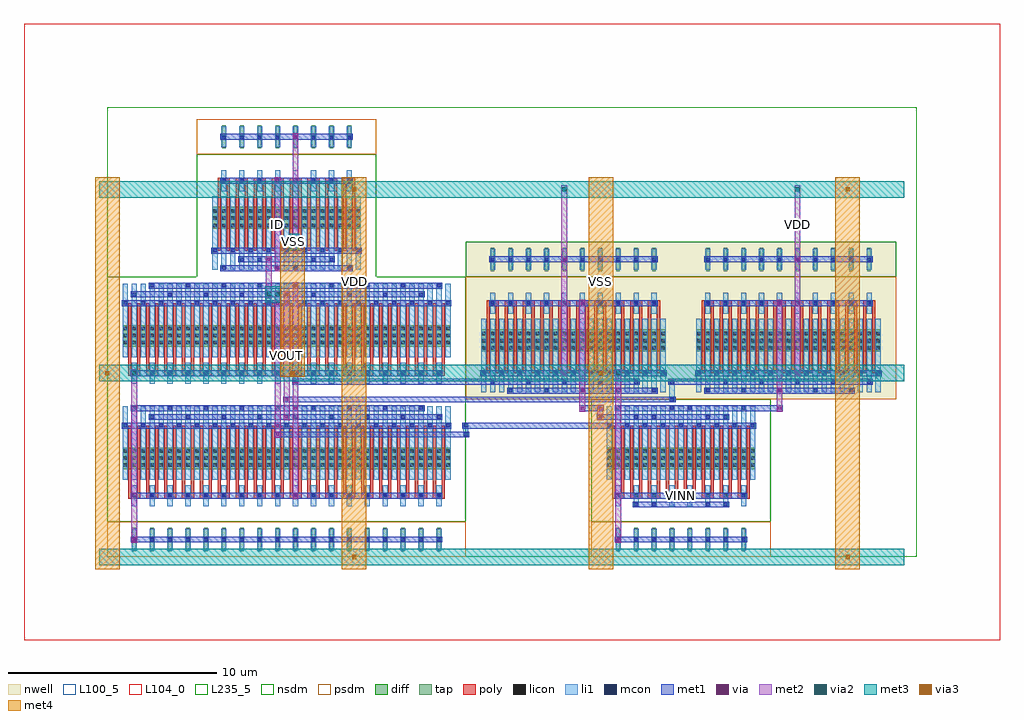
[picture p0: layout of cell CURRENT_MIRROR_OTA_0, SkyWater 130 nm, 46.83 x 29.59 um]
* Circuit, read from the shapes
.subckt CURRENT_MIRROR_OTA_0 ID VDD VINN VINP VOUT VSS
XM1 n1 n1 n2 VSS sky130_fd_pr__nfet_01v8 w=1.05 l=0.15 m=36
XM2 VOUT n1 n2 VSS sky130_fd_pr__nfet_01v8 w=1.05 l=0.15 m=36
XM3 ID ID VSS VSS sky130_fd_pr__nfet_01v8 w=1.05 l=0.15 m=8
XM4 n2 ID VSS VSS sky130_fd_pr__nfet_01v8 w=1.05 l=0.15 m=8
XM5 n3 VINN n2 VSS sky130_fd_pr__nfet_01v8 w=1.05 l=0.15 m=8
XM6 n4 VINP n2 VSS sky130_fd_pr__nfet_01v8 w=1.05 l=0.15 m=8
XM7 n1 n4 VDD VDD sky130_fd_pr__pfet_01v8 w=1.05 l=0.15 m=10
XM8 n4 n4 VDD VDD sky130_fd_pr__pfet_01v8 w=1.05 l=0.15 m=10
XM9 n3 n3 VDD VDD sky130_fd_pr__pfet_01v8 w=1.05 l=0.15 m=10
XM10 VOUT n3 VDD VDD sky130_fd_pr__pfet_01v8 w=1.05 l=0.15 m=10
.ends

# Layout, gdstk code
from math import pi, radians
import gdstk
lib = gdstk.Library(unit=1e-6, precision=1e-09)
def R(c, l, rs):  # rectangles x0, y0, x1, y1
    for r in rs: c.add(gdstk.rectangle(r[:2], r[2:], *l))
def A(c, l, x, y, w, h, nx, ny, dx, dy):  # array of equal rectangles
    R(c, l, [(x+i*dx, y+j*dy, x+i*dx+w, y+j*dy+h) for i in range(nx) for j in range(ny)])
def P(c, l, *ps):  # polygons
    for p in ps: c.add(gdstk.Polygon(p, *l))
nwell = (64, 20)
diff = (65, 20)
tap = (65, 44)
poly = (66, 20)
licon = (66, 44)
li1 = (67, 20)
mcon = (67, 44)
met1 = (68, 20)
via = (68, 44)
met2 = (69, 20)
via2 = (69, 44)
met3 = (70, 20)
via3 = (70, 44)
met4 = (71, 20)
nsdm = (93, 44)
psdm = (94, 20)
L100_5 = (100, 5)
L104_0 = (104, 0)
L235_5 = (235, 5)

scm_nmos_38434623_x4_y1_ = lib.new_cell('SCM_NMOS_38434623_X4_Y1_1725058283')
R(scm_nmos_38434623_x4_y1_, diff, [(0.735,2.31,7.865,3.36)])
A(scm_nmos_38434623_x4_y1_, tap, 1.205, 6.16, 0.17, 1.12, 8, 1, 0.86, 0)
A(scm_nmos_38434623_x4_y1_, poly, 1, 1.26, 0.15, 3.36, 16, 1, 0.43, 0)
A(scm_nmos_38434623_x4_y1_, poly, 1, 4.485, 0.58, 0.27, 8, 1, 0.86, 0)
A(scm_nmos_38434623_x4_y1_, licon, 0.775, 2.39, 0.17, 0.17, 3, 3, 0.43, 0.34)
A(scm_nmos_38434623_x4_y1_, licon, 1.635, 2.39, 0.17, 0.17, 3, 3, 0.43, 0.34)
A(scm_nmos_38434623_x4_y1_, licon, 2.495, 2.39, 0.17, 0.17, 3, 3, 0.43, 0.34)
A(scm_nmos_38434623_x4_y1_, licon, 3.355, 2.39, 0.17, 0.17, 3, 3, 0.43, 0.34)
A(scm_nmos_38434623_x4_y1_, licon, 4.215, 2.39, 0.17, 0.17, 3, 3, 0.43, 0.34)
A(scm_nmos_38434623_x4_y1_, licon, 5.075, 2.39, 0.17, 0.17, 3, 3, 0.43, 0.34)
A(scm_nmos_38434623_x4_y1_, licon, 5.935, 2.39, 0.17, 0.17, 3, 3, 0.43, 0.34)
A(scm_nmos_38434623_x4_y1_, licon, 6.795, 2.39, 0.17, 0.17, 3, 3, 0.43, 0.34)
A(scm_nmos_38434623_x4_y1_, licon, 1.205, 4.535, 0.17, 0.17, 8, 2, 0.86, 2.1)
A(scm_nmos_38434623_x4_y1_, li1, 0.735, 0.335, 0.25, 3.53, 17, 1, 0.43, 0)
A(scm_nmos_38434623_x4_y1_, li1, 1.165, 4.115, 0.25, 1.01, 8, 2, 0.86, 2.1)
A(scm_nmos_38434623_x4_y1_, mcon, 0.775, 1.175, 0.17, 0.17, 9, 1, 0.86, 0)
A(scm_nmos_38434623_x4_y1_, mcon, 1.205, 4.535, 0.17, 0.17, 8, 2, 0.86, 2.1)
R(scm_nmos_38434623_x4_y1_, mcon, [(1.205,0.335,1.375,0.505), (3.785,0.335,3.955,0.505), (4.645,0.335,4.815,0.505), (7.225,0.335,7.395,0.505), (2.065,0.755,2.235,0.925), (2.925,0.755,3.095,0.925), (5.505,0.755,5.675,0.925), (6.365,0.755,6.535,0.925)])
R(scm_nmos_38434623_x4_y1_, met1, [(1.12,0.28,7.48,0.56), (1.98,0.7,6.62,0.98), (0.69,1.12,7.91,1.4), (1.12,4.48,7.48,4.76), (1.12,6.58,7.48,6.86)])
R(scm_nmos_38434623_x4_y1_, via, [(3.795,0.345,3.945,0.495), (4.655,1.185,4.805,1.335), (3.795,4.545,3.945,4.695), (4.655,6.645,4.805,6.795)])
R(scm_nmos_38434623_x4_y1_, met2, [(3.73,0.26,4.01,4.78), (4.59,1.1,4.87,6.88)])
R(scm_nmos_38434623_x4_y1_, nsdm, [(0,0,8.6,5.88)])
R(scm_nmos_38434623_x4_y1_, psdm, [(0,5.88,8.6,7.56)])
R(scm_nmos_38434623_x4_y1_, L100_5, [(0,0,8.6,7.56)])

scm_pmos_61005845_x5_y1_ = lib.new_cell('SCM_PMOS_61005845_X5_Y1_1725058285')
R(scm_pmos_61005845_x5_y1_, nwell, [(0,0,10.32,7.56)])
R(scm_pmos_61005845_x5_y1_, diff, [(0.735,2.31,9.585,3.36)])
A(scm_pmos_61005845_x5_y1_, tap, 1.205, 6.16, 0.17, 1.12, 10, 1, 0.86, 0)
A(scm_pmos_61005845_x5_y1_, poly, 1, 1.26, 0.15, 3.36, 20, 1, 0.43, 0)
A(scm_pmos_61005845_x5_y1_, poly, 1, 4.485, 0.58, 0.27, 10, 1, 0.86, 0)
A(scm_pmos_61005845_x5_y1_, licon, 0.775, 2.39, 0.17, 0.17, 3, 3, 0.43, 0.34)
A(scm_pmos_61005845_x5_y1_, licon, 1.635, 2.39, 0.17, 0.17, 3, 3, 0.43, 0.34)
A(scm_pmos_61005845_x5_y1_, licon, 2.495, 2.39, 0.17, 0.17, 3, 3, 0.43, 0.34)
A(scm_pmos_61005845_x5_y1_, licon, 3.355, 2.39, 0.17, 0.17, 3, 3, 0.43, 0.34)
A(scm_pmos_61005845_x5_y1_, licon, 4.215, 2.39, 0.17, 0.17, 3, 3, 0.43, 0.34)
A(scm_pmos_61005845_x5_y1_, licon, 5.075, 2.39, 0.17, 0.17, 3, 3, 0.43, 0.34)
A(scm_pmos_61005845_x5_y1_, licon, 5.935, 2.39, 0.17, 0.17, 3, 3, 0.43, 0.34)
A(scm_pmos_61005845_x5_y1_, licon, 6.795, 2.39, 0.17, 0.17, 3, 3, 0.43, 0.34)
A(scm_pmos_61005845_x5_y1_, licon, 7.655, 2.39, 0.17, 0.17, 3, 3, 0.43, 0.34)
A(scm_pmos_61005845_x5_y1_, licon, 8.515, 2.39, 0.17, 0.17, 3, 3, 0.43, 0.34)
A(scm_pmos_61005845_x5_y1_, licon, 1.205, 4.535, 0.17, 0.17, 10, 2, 0.86, 2.1)
A(scm_pmos_61005845_x5_y1_, li1, 0.735, 0.335, 0.25, 3.53, 21, 1, 0.43, 0)
A(scm_pmos_61005845_x5_y1_, li1, 1.165, 4.115, 0.25, 1.01, 10, 2, 0.86, 2.1)
A(scm_pmos_61005845_x5_y1_, mcon, 1.205, 0.335, 0.17, 0.17, 5, 1, 1.72, 0)
A(scm_pmos_61005845_x5_y1_, mcon, 2.065, 0.755, 0.17, 0.17, 5, 1, 1.72, 0)
A(scm_pmos_61005845_x5_y1_, mcon, 0.775, 1.175, 0.17, 0.17, 11, 1, 0.86, 0)
A(scm_pmos_61005845_x5_y1_, mcon, 1.205, 4.535, 0.17, 0.17, 10, 2, 0.86, 2.1)
R(scm_pmos_61005845_x5_y1_, met1, [(1.12,0.28,8.34,0.56), (1.98,0.7,9.2,0.98), (0.69,1.12,9.63,1.4), (1.12,4.48,9.2,4.76), (1.12,6.58,9.2,6.86)])
R(scm_pmos_61005845_x5_y1_, via, [(4.655,0.345,4.805,0.495), (5.515,1.185,5.665,1.335), (4.655,4.545,4.805,4.695), (5.515,6.645,5.665,6.795)])
R(scm_pmos_61005845_x5_y1_, met2, [(4.59,0.26,4.87,4.78), (5.45,1.1,5.73,6.88)])
R(scm_pmos_61005845_x5_y1_, nsdm, [(0,5.88,10.32,7.56)])
R(scm_pmos_61005845_x5_y1_, psdm, [(0,0,10.32,5.88)])
R(scm_pmos_61005845_x5_y1_, L100_5, [(0,0,10.32,7.56)])

scm_nmos_b_8106910_x9_y2 = lib.new_cell('SCM_NMOS_B_8106910_X9_Y2_1725058284')
R(scm_nmos_b_8106910_x9_y2, diff, [(0.735,2.31,16.465,3.36), (0.735,8.19,16.465,9.24)])
A(scm_nmos_b_8106910_x9_y2, tap, 1.205, 12.04, 0.17, 1.12, 18, 1, 0.86, 0)
A(scm_nmos_b_8106910_x9_y2, poly, 1, 1.26, 0.15, 3.36, 36, 2, 0.43, 5.88)
A(scm_nmos_b_8106910_x9_y2, poly, 1, 4.485, 0.58, 0.27, 18, 2, 0.86, 5.88)
A(scm_nmos_b_8106910_x9_y2, licon, 0.775, 2.39, 0.17, 0.17, 3, 3, 0.43, 0.34)
A(scm_nmos_b_8106910_x9_y2, licon, 1.635, 2.39, 0.17, 0.17, 3, 3, 0.43, 0.34)
A(scm_nmos_b_8106910_x9_y2, licon, 2.495, 2.39, 0.17, 0.17, 3, 3, 0.43, 0.34)
A(scm_nmos_b_8106910_x9_y2, licon, 3.355, 2.39, 0.17, 0.17, 3, 3, 0.43, 0.34)
A(scm_nmos_b_8106910_x9_y2, licon, 4.215, 2.39, 0.17, 0.17, 3, 3, 0.43, 0.34)
A(scm_nmos_b_8106910_x9_y2, licon, 5.075, 2.39, 0.17, 0.17, 3, 3, 0.43, 0.34)
A(scm_nmos_b_8106910_x9_y2, licon, 5.935, 2.39, 0.17, 0.17, 3, 3, 0.43, 0.34)
A(scm_nmos_b_8106910_x9_y2, licon, 6.795, 2.39, 0.17, 0.17, 3, 3, 0.43, 0.34)
A(scm_nmos_b_8106910_x9_y2, licon, 7.655, 2.39, 0.17, 0.17, 3, 3, 0.43, 0.34)
A(scm_nmos_b_8106910_x9_y2, licon, 8.515, 2.39, 0.17, 0.17, 3, 3, 0.43, 0.34)
A(scm_nmos_b_8106910_x9_y2, licon, 9.375, 2.39, 0.17, 0.17, 3, 3, 0.43, 0.34)
A(scm_nmos_b_8106910_x9_y2, licon, 10.235, 2.39, 0.17, 0.17, 3, 3, 0.43, 0.34)
A(scm_nmos_b_8106910_x9_y2, licon, 11.095, 2.39, 0.17, 0.17, 3, 3, 0.43, 0.34)
A(scm_nmos_b_8106910_x9_y2, licon, 11.955, 2.39, 0.17, 0.17, 3, 3, 0.43, 0.34)
A(scm_nmos_b_8106910_x9_y2, licon, 12.815, 2.39, 0.17, 0.17, 3, 3, 0.43, 0.34)
A(scm_nmos_b_8106910_x9_y2, licon, 13.675, 2.39, 0.17, 0.17, 3, 3, 0.43, 0.34)
A(scm_nmos_b_8106910_x9_y2, licon, 14.535, 2.39, 0.17, 0.17, 3, 3, 0.43, 0.34)
A(scm_nmos_b_8106910_x9_y2, licon, 15.395, 2.39, 0.17, 0.17, 3, 3, 0.43, 0.34)
A(scm_nmos_b_8106910_x9_y2, licon, 1.205, 4.535, 0.17, 0.17, 18, 2, 0.86, 5.88)
A(scm_nmos_b_8106910_x9_y2, licon, 0.775, 8.27, 0.17, 0.17, 3, 3, 0.43, 0.34)
A(scm_nmos_b_8106910_x9_y2, licon, 1.635, 8.27, 0.17, 0.17, 3, 3, 0.43, 0.34)
A(scm_nmos_b_8106910_x9_y2, licon, 2.495, 8.27, 0.17, 0.17, 3, 3, 0.43, 0.34)
A(scm_nmos_b_8106910_x9_y2, licon, 3.355, 8.27, 0.17, 0.17, 3, 3, 0.43, 0.34)
A(scm_nmos_b_8106910_x9_y2, licon, 4.215, 8.27, 0.17, 0.17, 3, 3, 0.43, 0.34)
A(scm_nmos_b_8106910_x9_y2, licon, 5.075, 8.27, 0.17, 0.17, 3, 3, 0.43, 0.34)
A(scm_nmos_b_8106910_x9_y2, licon, 5.935, 8.27, 0.17, 0.17, 3, 3, 0.43, 0.34)
A(scm_nmos_b_8106910_x9_y2, licon, 6.795, 8.27, 0.17, 0.17, 3, 3, 0.43, 0.34)
A(scm_nmos_b_8106910_x9_y2, licon, 7.655, 8.27, 0.17, 0.17, 3, 3, 0.43, 0.34)
A(scm_nmos_b_8106910_x9_y2, licon, 8.515, 8.27, 0.17, 0.17, 3, 3, 0.43, 0.34)
A(scm_nmos_b_8106910_x9_y2, licon, 9.375, 8.27, 0.17, 0.17, 3, 3, 0.43, 0.34)
A(scm_nmos_b_8106910_x9_y2, licon, 10.235, 8.27, 0.17, 0.17, 3, 3, 0.43, 0.34)
A(scm_nmos_b_8106910_x9_y2, licon, 11.095, 8.27, 0.17, 0.17, 3, 3, 0.43, 0.34)
A(scm_nmos_b_8106910_x9_y2, licon, 11.955, 8.27, 0.17, 0.17, 3, 3, 0.43, 0.34)
A(scm_nmos_b_8106910_x9_y2, licon, 12.815, 8.27, 0.17, 0.17, 3, 3, 0.43, 0.34)
A(scm_nmos_b_8106910_x9_y2, licon, 13.675, 8.27, 0.17, 0.17, 3, 3, 0.43, 0.34)
A(scm_nmos_b_8106910_x9_y2, licon, 14.535, 8.27, 0.17, 0.17, 3, 3, 0.43, 0.34)
A(scm_nmos_b_8106910_x9_y2, licon, 15.395, 8.27, 0.17, 0.17, 3, 3, 0.43, 0.34)
R(scm_nmos_b_8106910_x9_y2, licon, [(1.205,12.515,1.375,12.685), (1.205,12.515,1.375,12.685), (2.065,12.515,2.235,12.685), (2.065,12.515,2.235,12.685), (2.925,12.515,3.095,12.685), (2.925,12.515,3.095,12.685), (3.785,12.515,3.955,12.685), (3.785,12.515,3.955,12.685), (4.645,12.515,4.815,12.685), (4.645,12.515,4.815,12.685), (5.505,12.515,5.675,12.685), (5.505,12.515,5.675,12.685), (6.365,12.515,6.535,12.685), (6.365,12.515,6.535,12.685), (7.225,12.515,7.395,12.685), (7.225,12.515,7.395,12.685), (8.085,12.515,8.255,12.685), (8.085,12.515,8.255,12.685), (8.945,12.515,9.115,12.685), (8.945,12.515,9.115,12.685), (9.805,12.515,9.975,12.685), (9.805,12.515,9.975,12.685), (10.665,12.515,10.835,12.685), (10.665,12.515,10.835,12.685), (11.525,12.515,11.695,12.685), (11.525,12.515,11.695,12.685), (12.385,12.515,12.555,12.685), (12.385,12.515,12.555,12.685), (13.245,12.515,13.415,12.685), (13.245,12.515,13.415,12.685), (14.105,12.515,14.275,12.685), (14.105,12.515,14.275,12.685), (14.965,12.515,15.135,12.685), (14.965,12.515,15.135,12.685), (15.825,12.515,15.995,12.685), (15.825,12.515,15.995,12.685)])
A(scm_nmos_b_8106910_x9_y2, li1, 0.735, 0.335, 0.25, 3.53, 37, 2, 0.43, 5.88)
A(scm_nmos_b_8106910_x9_y2, li1, 1.165, 4.115, 0.25, 1.01, 18, 2, 0.86, 5.88)
A(scm_nmos_b_8106910_x9_y2, li1, 1.165, 12.095, 0.25, 1.01, 18, 1, 0.86, 0)
A(scm_nmos_b_8106910_x9_y2, mcon, 1.205, 0.335, 0.17, 0.17, 9, 2, 1.72, 6.3)
A(scm_nmos_b_8106910_x9_y2, mcon, 2.065, 0.755, 0.17, 0.17, 9, 2, 1.72, 5.46)
A(scm_nmos_b_8106910_x9_y2, mcon, 0.775, 1.175, 0.17, 0.17, 19, 2, 0.86, 5.88)
A(scm_nmos_b_8106910_x9_y2, mcon, 1.205, 4.535, 0.17, 0.17, 18, 2, 0.86, 5.88)
A(scm_nmos_b_8106910_x9_y2, mcon, 1.205, 12.515, 0.17, 0.17, 18, 1, 0.86, 0)
R(scm_nmos_b_8106910_x9_y2, met1, [(1.12,0.28,15.22,0.56), (1.98,0.7,16.08,0.98), (0.69,1.12,16.51,1.4), (1.12,4.48,16.08,4.76), (1.98,6.16,16.08,6.44), (1.12,6.58,15.22,6.86), (0.69,7,16.51,7.28), (1.12,10.36,16.08,10.64), (1.12,12.46,16.08,12.74)])
R(scm_nmos_b_8106910_x9_y2, via, [(8.095,0.345,8.245,0.495), (8.525,0.765,8.675,0.915), (8.955,1.185,9.105,1.335), (8.095,4.545,8.245,4.695), (8.095,6.225,8.245,6.375), (8.525,6.645,8.675,6.795), (8.955,7.065,9.105,7.215), (8.095,10.425,8.245,10.575)])
R(scm_nmos_b_8106910_x9_y2, met2, [(8.03,0.26,8.31,10.66), (8.46,0.68,8.74,6.88), (8.89,1.1,9.17,7.3)])
R(scm_nmos_b_8106910_x9_y2, nsdm, [(0,0,17.2,11.76)])
R(scm_nmos_b_8106910_x9_y2, psdm, [(0,11.76,17.2,13.44)])
R(scm_nmos_b_8106910_x9_y2, L100_5, [(0,0,17.2,13.44)])

dp_nmos_b_13499319_x4_y1 = lib.new_cell('DP_NMOS_B_13499319_X4_Y1_1725058282')
R(dp_nmos_b_13499319_x4_y1, diff, [(0.735,2.31,7.865,3.36)])
A(dp_nmos_b_13499319_x4_y1, tap, 1.205, 6.16, 0.17, 1.12, 8, 1, 0.86, 0)
A(dp_nmos_b_13499319_x4_y1, poly, 1, 1.26, 0.15, 3.36, 16, 1, 0.43, 0)
A(dp_nmos_b_13499319_x4_y1, poly, 1, 4.485, 0.58, 0.27, 8, 1, 0.86, 0)
A(dp_nmos_b_13499319_x4_y1, licon, 0.775, 2.39, 0.17, 0.17, 3, 3, 0.43, 0.34)
A(dp_nmos_b_13499319_x4_y1, licon, 1.635, 2.39, 0.17, 0.17, 3, 3, 0.43, 0.34)
A(dp_nmos_b_13499319_x4_y1, licon, 2.495, 2.39, 0.17, 0.17, 3, 3, 0.43, 0.34)
A(dp_nmos_b_13499319_x4_y1, licon, 3.355, 2.39, 0.17, 0.17, 3, 3, 0.43, 0.34)
A(dp_nmos_b_13499319_x4_y1, licon, 4.215, 2.39, 0.17, 0.17, 3, 3, 0.43, 0.34)
A(dp_nmos_b_13499319_x4_y1, licon, 5.075, 2.39, 0.17, 0.17, 3, 3, 0.43, 0.34)
A(dp_nmos_b_13499319_x4_y1, licon, 5.935, 2.39, 0.17, 0.17, 3, 3, 0.43, 0.34)
A(dp_nmos_b_13499319_x4_y1, licon, 6.795, 2.39, 0.17, 0.17, 3, 3, 0.43, 0.34)
A(dp_nmos_b_13499319_x4_y1, licon, 1.205, 4.535, 0.17, 0.17, 8, 2, 0.86, 2.1)
A(dp_nmos_b_13499319_x4_y1, li1, 0.735, 0.335, 0.25, 3.53, 17, 1, 0.43, 0)
A(dp_nmos_b_13499319_x4_y1, li1, 1.165, 4.115, 0.25, 1.01, 8, 2, 0.86, 2.1)
A(dp_nmos_b_13499319_x4_y1, mcon, 0.775, 1.175, 0.17, 0.17, 9, 1, 0.86, 0)
A(dp_nmos_b_13499319_x4_y1, mcon, 1.205, 6.635, 0.17, 0.17, 8, 1, 0.86, 0)
R(dp_nmos_b_13499319_x4_y1, mcon, [(1.205,0.335,1.375,0.505), (3.785,0.335,3.955,0.505), (4.645,0.335,4.815,0.505), (7.225,0.335,7.395,0.505), (2.065,0.755,2.235,0.925), (2.925,0.755,3.095,0.925), (5.505,0.755,5.675,0.925), (6.365,0.755,6.535,0.925), (1.205,4.535,1.375,4.705), (3.785,4.535,3.955,4.705), (4.645,4.535,4.815,4.705), (7.225,4.535,7.395,4.705), (2.065,4.955,2.235,5.125), (2.925,4.955,3.095,5.125), (5.505,4.955,5.675,5.125), (6.365,4.955,6.535,5.125)])
R(dp_nmos_b_13499319_x4_y1, met1, [(1.12,0.28,7.48,0.56), (1.98,0.7,6.62,0.98), (0.69,1.12,7.91,1.4), (1.12,4.48,7.48,4.76), (1.98,4.9,6.62,5.18), (1.12,6.58,7.48,6.86)])
R(dp_nmos_b_13499319_x4_y1, nsdm, [(0,0,8.6,5.88)])
R(dp_nmos_b_13499319_x4_y1, psdm, [(0,5.88,8.6,7.56)])
R(dp_nmos_b_13499319_x4_y1, L100_5, [(0,0,8.6,7.56)])

current_mirror_ota_0 = lib.new_cell('CURRENT_MIRROR_OTA_0')
R(current_mirror_ota_0, li1, [(17.075,5.795,17.325,5.965), (17.075,5.795,17.325,5.965), (17.075,5.88,17.325,6.3), (17.075,6.215,17.325,6.385), (17.075,6.215,17.325,6.385), (26.965,7.475,27.215,7.645), (26.965,7.475,27.215,7.645), (26.965,7.56,27.215,8.4), (26.965,8.315,27.215,8.485), (26.965,8.315,27.215,8.485)])
R(current_mirror_ota_0, mcon, [(17.115,5.795,17.285,5.965), (17.115,5.795,17.285,5.965), (17.115,6.215,17.285,6.385), (17.115,6.215,17.285,6.385), (27.005,7.475,27.175,7.645), (27.005,7.475,27.175,7.645), (27.005,8.315,27.175,8.485), (27.005,8.315,27.175,8.485)])
R(current_mirror_ota_0, met1, [(1.13,0.7,1.45,0.98), (1.13,0.7,1.45,0.98), (1.13,0.7,1.45,0.98), (24.35,0.7,24.67,0.98), (24.35,0.7,24.67,0.98), (8.01,5.74,8.33,6.02), (8.01,5.74,8.33,6.02), (8.17,5.74,17.2,6.02), (17.03,5.74,17.37,6.02), (17.03,5.74,17.37,6.02), (17.03,6.16,17.37,6.44), (17.03,6.16,17.37,6.44), (17.2,6.16,24.08,6.44), (23.49,6.58,23.81,6.86), (23.49,6.58,23.81,6.86), (23.65,6.58,25.37,6.86), (22.63,7,22.95,7.28), (22.63,7,22.95,7.28), (22.79,7,23.65,7.28), (23.49,7,23.81,7.28), (23.49,7,23.81,7.28), (30.53,7,32.25,7.28), (32.09,7,32.41,7.28), (32.09,7,32.41,7.28), (8.44,7.42,8.76,7.7), (8.44,7.42,8.76,7.7), (8.6,7.42,27.09,7.7), (26.92,7.42,27.26,7.7), (26.92,7.42,27.26,7.7), (8.87,8.26,9.19,8.54), (8.87,8.26,9.19,8.54), (9.03,8.26,18.49,8.54), (26.92,8.26,27.26,8.54), (26.92,8.26,27.26,8.54), (27.09,8.26,29.67,8.54), (7.58,14.14,7.9,14.42), (7.58,14.14,7.9,14.42), (7.58,14.14,7.9,14.42), (7.58,14.14,7.9,14.42)])
P(current_mirror_ota_0, met1, [(0,0),(0,0),(0,0),(0,0)],
  [(0,0),(0,0),(0,0),(0,0)],
  [(0,0),(0,0),(0,0),(0,0)],
  [(0,0),(0,0),(0,0),(0,0)],
  [(0,0),(0,0),(0,0),(0,0)],
  [(0,0),(0,0),(0,0),(0,0)],
  [(0,0),(0,0),(0,0),(0,0)],
  [(0,0),(0,0),(0,0),(0,0)],
  [(0,0),(0,0),(0,0),(0,0)],
  [(0,0),(0,0),(0,0),(0,0)],
  [(0,0),(0,0),(0,0),(0,0)],
  [(0,0),(0,0),(0,0),(0,0)])
R(current_mirror_ota_0, via, [(1.215,0.765,1.365,0.915), (1.215,0.765,1.365,0.915), (1.215,0.765,1.365,0.915), (24.435,0.765,24.585,0.915), (24.435,0.765,24.585,0.915), (8.095,5.805,8.245,5.955), (8.095,5.805,8.245,5.955), (23.575,6.645,23.725,6.795), (23.575,6.645,23.725,6.795), (22.715,7.065,22.865,7.215), (22.715,7.065,22.865,7.215), (23.575,7.065,23.725,7.215), (23.575,7.065,23.725,7.215), (32.175,7.065,32.325,7.215), (32.175,7.065,32.325,7.215), (8.525,7.485,8.675,7.635), (8.525,7.485,8.675,7.635), (8.955,8.325,9.105,8.475), (8.955,8.325,9.105,8.475), (7.665,14.205,7.815,14.355), (7.665,14.205,7.815,14.355), (7.665,14.205,7.815,14.355), (7.665,14.205,7.815,14.355)])
R(current_mirror_ota_0, met2, [(1.15,0.68,1.43,1), (1.15,0.68,1.43,1), (1.15,0.68,1.43,1), (24.37,0.68,24.65,1), (24.37,0.68,24.65,1), (1.15,0.84,1.43,8.82), (24.37,0.84,24.65,8.82), (8.03,5.72,8.31,6.04), (8.03,5.72,8.31,6.04), (8.03,5.88,8.31,6.3), (23.51,6.56,23.79,6.88), (23.51,6.56,23.79,6.88), (23.51,6.72,23.79,7.14), (22.65,6.98,22.93,7.3), (22.65,6.98,22.93,7.3), (23.51,6.98,23.79,7.3), (23.51,6.98,23.79,7.3), (32.11,6.98,32.39,7.3), (32.11,6.98,32.39,7.3), (22.65,7.14,22.93,7.98), (32.11,7.14,32.39,7.98), (8.46,7.4,8.74,7.72), (8.46,7.4,8.74,7.72), (8.89,8.24,9.17,8.56), (8.89,8.24,9.17,8.56), (1.15,8.635,1.43,9.005), (1.15,8.635,1.43,9.005), (1.15,8.635,1.43,9.005), (24.37,8.635,24.65,9.005), (24.37,8.635,24.65,9.005), (8.03,12.18,8.31,12.6), (7.6,12.415,7.88,12.785), (7.6,12.415,7.88,12.785), (7.6,12.415,7.88,12.785), (7.6,12.415,7.88,12.785), (8.03,12.415,8.31,12.785), (8.03,12.415,8.31,12.785), (8.03,12.415,8.31,12.785), (8.03,12.415,8.31,12.785), (7.6,12.6,7.88,14.28), (7.6,14.12,7.88,14.44), (7.6,14.12,7.88,14.44), (7.6,14.12,7.88,14.44), (7.6,14.12,7.88,14.44), (21.79,14.28,22.07,17.64), (32.97,14.28,33.25,17.64), (8.89,14.935,9.17,15.305), (21.79,17.455,22.07,17.825), (21.79,17.455,22.07,17.825), (32.97,17.455,33.25,17.825), (32.97,17.455,33.25,17.825), (32.97,17.455,33.25,17.825)])
P(current_mirror_ota_0, met2, [(0,0),(0,0),(0,0),(0,0)],
  [(0,0),(0,0),(0,0),(0,0)],
  [(0,0),(0,0),(0,0),(0,0)],
  [(0,0),(0,0),(0,0),(0,0)],
  [(0,0),(0,0),(0,0),(0,0)],
  [(0,0),(0,0),(0,0),(0,0)],
  [(0,0),(0,0),(0,0),(0,0)],
  [(0,0),(0,0),(0,0),(0,0)],
  [(0,0),(0,0),(0,0),(0,0)],
  [(0,0),(0,0),(0,0),(0,0)],
  [(0,0),(0,0),(0,0),(0,0)])
R(current_mirror_ota_0, via2, [(1.19,8.72,1.39,8.92), (1.19,8.72,1.39,8.92), (1.19,8.72,1.39,8.92), (24.41,8.72,24.61,8.92), (24.41,8.72,24.61,8.92), (7.64,12.5,7.84,12.7), (7.64,12.5,7.84,12.7), (7.64,12.5,7.84,12.7), (7.64,12.5,7.84,12.7), (8.07,12.5,8.27,12.7), (8.07,12.5,8.27,12.7), (8.07,12.5,8.27,12.7), (8.07,12.5,8.27,12.7), (8.93,15.02,9.13,15.22), (21.83,17.54,22.03,17.74), (21.83,17.54,22.03,17.74), (33.01,17.54,33.21,17.74), (33.01,17.54,33.21,17.74), (33.01,17.54,33.21,17.74)])
A(current_mirror_ota_0, met3, -0.4, -0.4, 4.24, 0.8, 3, 3, 3.44, 8.82)
A(current_mirror_ota_0, met3, 9.92, -0.4, 2.32, 0.8, 1, 3, 0, 8.82)
A(current_mirror_ota_0, met3, 11.44, -0.4, 2.72, 0.8, 1, 3, 0, 8.82)
A(current_mirror_ota_0, met3, 13.36, -0.4, 4.24, 0.8, 1, 3, 0, 8.82)
A(current_mirror_ota_0, met3, 16.8, -0.4, 4.24, 0.8, 1, 3, 0, 8.82)
A(current_mirror_ota_0, met3, 20.24, -0.4, 3.84, 0.8, 1, 3, 0, 8.82)
A(current_mirror_ota_0, met3, 23.28, -0.4, 1.2, 0.8, 1, 3, 0, 8.82)
A(current_mirror_ota_0, met3, 23.68, -0.4, 4.24, 0.8, 3, 3, 3.44, 8.82)
A(current_mirror_ota_0, met3, 34, -0.4, 1.92, 0.8, 1, 3, 0, 8.82)
A(current_mirror_ota_0, met3, 35.12, -0.4, 3.12, 0.8, 1, 3, 0, 8.82)
R(current_mirror_ota_0, met3, [(11.675,-0.4,12.005,0.4), (35.355,-0.4,35.685,0.4), (-0.165,8.42,0.165,9.22), (1.125,8.42,1.455,9.22), (1.125,8.42,1.455,9.22), (1.125,8.42,1.455,9.22), (8.715,8.42,9.045,9.22), (8.715,8.42,9.045,9.22), (8.715,8.42,9.045,9.22), (8.715,8.42,9.045,9.22), (23.515,8.42,23.845,9.22), (24.345,8.42,24.675,9.22), (24.345,8.42,24.675,9.22), (7.575,12.2,7.905,13), (7.575,12.2,7.905,13), (7.575,12.2,7.905,13), (7.575,12.2,7.905,13), (7.74,12.2,8.17,13), (8.005,12.2,8.335,13), (8.005,12.2,8.335,13), (8.005,12.2,8.335,13), (8.005,12.2,8.335,13), (8.715,14.72,9.045,15.52), (8.805,14.72,9.105,15.52), (8.865,14.72,9.195,15.52), (11.675,17.24,12.005,18.04), (21.765,17.24,22.095,18.04), (21.765,17.24,22.095,18.04), (32.945,17.24,33.275,18.04), (32.945,17.24,33.275,18.04), (32.945,17.24,33.275,18.04), (35.355,17.24,35.685,18.04)])
R(current_mirror_ota_0, via3, [(11.74,-0.1,11.94,0.1), (35.42,-0.1,35.62,0.1), (-0.1,8.72,0.1,8.92), (8.78,8.72,8.98,8.92), (8.78,8.72,8.98,8.92), (8.78,8.72,8.98,8.92), (8.78,8.72,8.98,8.92), (23.58,8.72,23.78,8.92), (8.78,15.02,8.98,15.22), (11.74,17.54,11.94,17.74), (35.42,17.54,35.62,17.74)])
A(current_mirror_ota_0, met4, -0.59, -0.59, 1.18, 10, 4, 2, 11.84, 8.82)
R(current_mirror_ota_0, met4, [(11.25,-0.165,12.43,0.165), (34.93,-0.165,36.11,0.165), (-0.59,8.655,0.59,8.985), (8.29,8.655,9.47,8.985), (8.29,8.655,9.47,8.985), (8.29,8.655,9.47,8.985), (8.29,8.655,9.47,8.985), (23.09,8.655,24.27,8.985), (8.29,8.82,9.47,15.12), (8.29,14.955,9.47,15.285), (11.25,17.475,12.43,17.805), (34.93,17.475,36.11,17.805)])
R(current_mirror_ota_0, L104_0, [(-4,-4,42.83,25.59)])
R(current_mirror_ota_0, L235_5, [(0,0,38.83,21.59)])
current_mirror_ota_0.add(gdstk.Reference(scm_nmos_38434623_x4_y1_, (4.3,13.44)))
current_mirror_ota_0.add(gdstk.Reference(scm_pmos_61005845_x5_y1_, (27.52,7.56)))
current_mirror_ota_0.add(gdstk.Reference(scm_pmos_61005845_x5_y1_, (27.52,7.56), rotation=pi, x_reflection=True))
current_mirror_ota_0.add(gdstk.Reference(scm_nmos_b_8106910_x9_y2, (17.2,13.44), rotation=pi))
current_mirror_ota_0.add(gdstk.Reference(dp_nmos_b_13499319_x4_y1, (23.22,7.56), x_reflection=True))
current_mirror_ota_0.add(gdstk.Label('ID', (8.17,15.96), layer=69, texttype=5))
current_mirror_ota_0.add(gdstk.Label('VOUT', (8.6,9.66), layer=69, texttype=5))
current_mirror_ota_0.add(gdstk.Label('VINN', (27.52,2.94), layer=68, texttype=5))
current_mirror_ota_0.add(gdstk.Label('VINP', (27.52,2.52), layer=68, texttype=5))
current_mirror_ota_0.add(gdstk.Label('VSS', (23.68,13.23), layer=71, texttype=5))
current_mirror_ota_0.add(gdstk.Label('VSS', (8.955,15.12), layer=70, texttype=5))
current_mirror_ota_0.add(gdstk.Label('VSS', (23.68,13.23), layer=71, texttype=5))
current_mirror_ota_0.add(gdstk.Label('VSS', (23.68,13.23), layer=71, texttype=5))
current_mirror_ota_0.add(gdstk.Label('VSS', (23.68,13.23), layer=71, texttype=5))
current_mirror_ota_0.add(gdstk.Label('VSS', (23.68,13.23), layer=71, texttype=5))
current_mirror_ota_0.add(gdstk.Label('VSS', (23.68,13.23), layer=71, texttype=5))
current_mirror_ota_0.add(gdstk.Label('VSS', (23.68,13.23), layer=71, texttype=5))
current_mirror_ota_0.add(gdstk.Label('VSS', (23.68,13.23), layer=71, texttype=5))
current_mirror_ota_0.add(gdstk.Label('VSS', (23.68,13.23), layer=71, texttype=5))
current_mirror_ota_0.add(gdstk.Label('VSS', (23.68,13.23), layer=71, texttype=5))
current_mirror_ota_0.add(gdstk.Label('VDD', (33.11,15.96), layer=69, texttype=5))
current_mirror_ota_0.add(gdstk.Label('VDD', (11.84,13.23), layer=71, texttype=5))
current_mirror_ota_0.add(gdstk.Label('VDD', (11.84,13.23), layer=71, texttype=5))
current_mirror_ota_0.add(gdstk.Label('VDD', (11.84,13.23), layer=71, texttype=5))
current_mirror_ota_0.add(gdstk.Label('VDD', (11.84,13.23), layer=71, texttype=5))

lib.write_gds('CURRENT_MIRROR_OTA_0.gds')
